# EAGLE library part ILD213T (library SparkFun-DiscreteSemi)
Dual optoisolator.

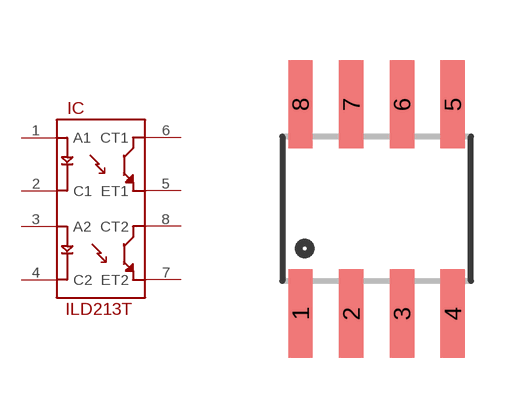
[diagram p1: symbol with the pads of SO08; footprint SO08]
Designator prefix IC

## ILD213T  [SO08]
1  A1
2  C1
3  A2
4  C2
5  ET1
6  CT1
7  ET2
8  CT2

## Footprint SO08 (pad centres in mm)
Small Outline Package Fits JEDEC packages (narrow SOIC-8)
smd 0.61 x 2.21: 1 -1.905,-2.616; 2 -0.635,-2.616; 3 0.635,-2.616; 4 1.905,-2.616; 5 1.905,2.616; 6 0.635,2.616; 7 -0.635,2.616; 8 -1.905,2.616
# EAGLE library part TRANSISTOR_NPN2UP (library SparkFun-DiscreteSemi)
2-up package of NPN transistors MMDT3904- TRANS-09373 (SOT-363, 200mA 40V)

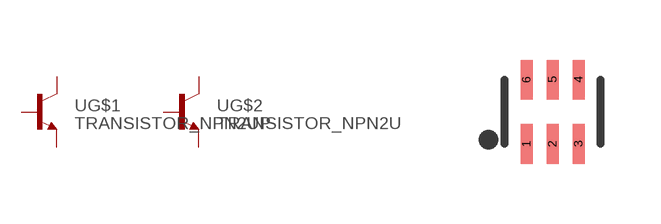
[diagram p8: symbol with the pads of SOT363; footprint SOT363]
Designator prefix -; gates G$1=NPN G$2=NPN

## TRANSISTOR_NPN2UPMMDT3904 (PROD_ID: TRANS-09373; VALUE: MMDT3904)  [SOT363]
1  G$1:E  pas
2  G$1:B  pas
3  G$2:C  pas
4  G$2:E  pas
5  G$2:B  pas
6  G$1:C  pas

## Footprint SOT363 (pad centres in mm)
smd 0.3 x 0.99: 1 -0.65,-0.8; 2 0,-0.8; 3 0.65,-0.8; 4 0.65,0.81; 5 0,0.81; 6 -0.65,0.81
